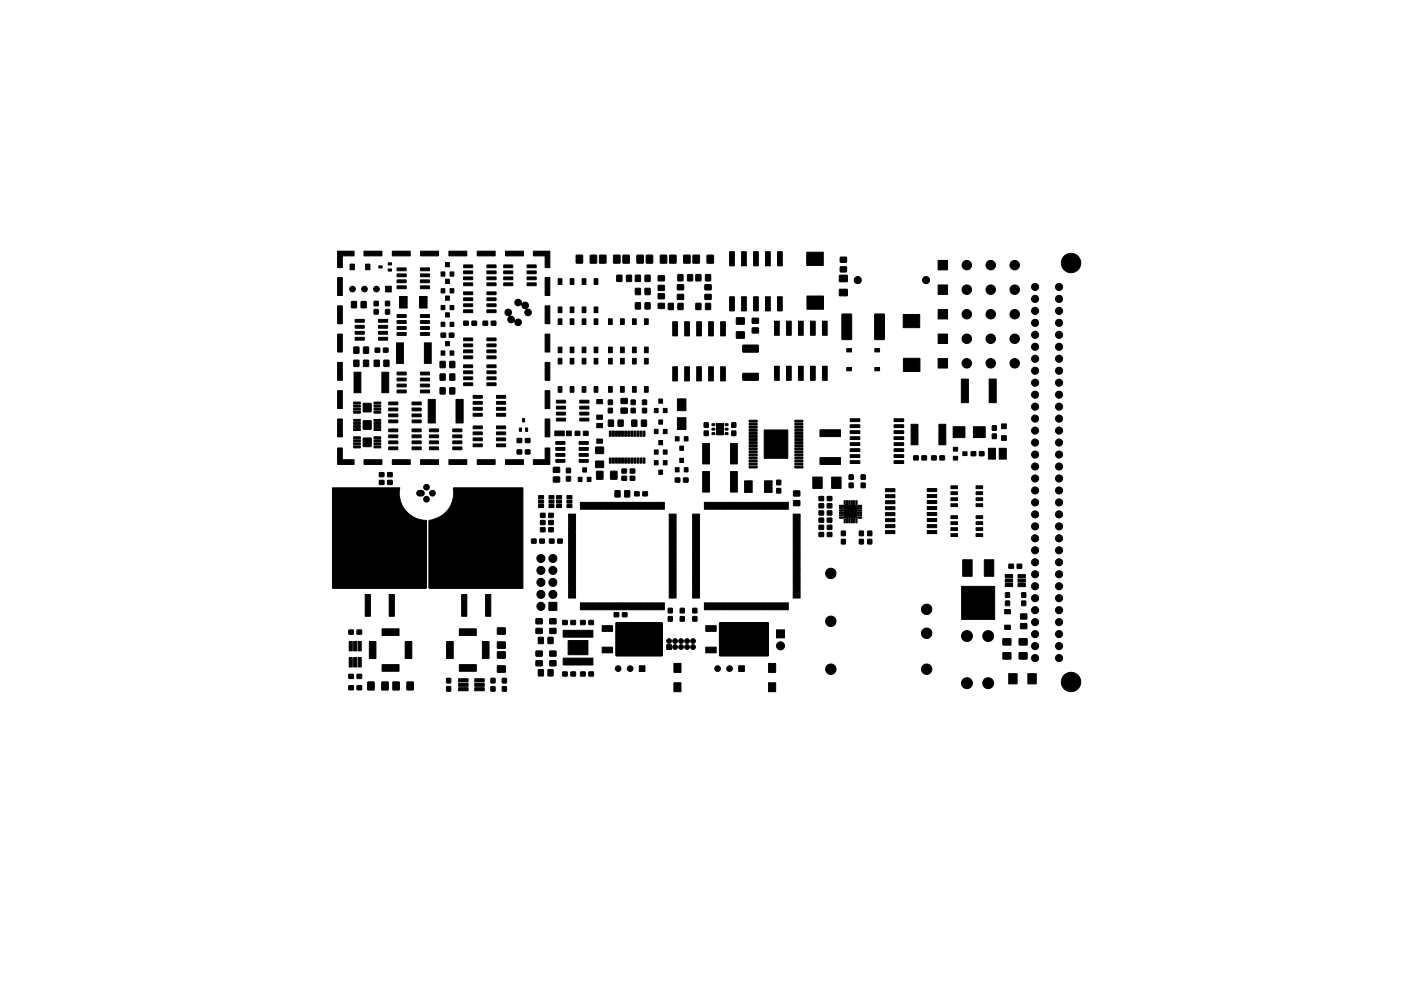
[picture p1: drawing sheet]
<svg xmlns="http://www.w3.org/2000/svg" width="297mm" height="210mm" viewBox="0 0 297 210" stroke-linecap="round" stroke-linejoin="round" font-family="sans-serif">
<g fill="#000" stroke="#000" stroke-width=".21">
<path d="M71.6 53.3h3.5v1h-2.5v2.5h-1zM74.2 56h.9v1.2h-.9zM77.5 56h.9v1.2h-.9zM77.2 53.3h3.8v1h-3.8zM80.3 56.4h.7v.5h-.7zM82.3 57.1h.7v.4h-.7zM82.3 55.8h.7v.4h-.7zM84.2 59.4h1.9v.5l-1.8 .1zM84.2 58.1h1.9v.5l-1.8 .1zM84.2 56.9l1.9-.1v.6h-1.8zM83.2 53.3h3.8v1h-3.8zM89.2 59.4h1.8l.1 .5-1.9 .1z"/>
<path d="M89.2 58.1h1.8l.1 .5-1.9 .1zM89.2 56.9l1.8-.1 .1 .6h-1.9zM89.2 53.3h3.8v1h-3.8zM93.5 57.7h.8v.9h-.8zM94.5 55.7h.8v.9h-.8zM95.4 57.7h.8v.9h-.8zM95.2 53.3h3.8v1h-3.8zM98.3 58.8h1.9v.5h-1.9zM98.3 57.5h1.9v.5l-1.9 .1zM98.3 56.2h1.9v.5l-1.9 .1zM101.2 53.3h3.8v1h-3.8zM103.3 58.8h1.8l.1 .5h-1.9z"/>
<path d="M103.3 57.5h1.8l.1 .5-1.9 .1zM103.3 56.2h1.8l.1 .5-1.9 .1zM106.8 58.8h1.9v.5h-1.8zM106.8 57.5h1.9v.5l-1.8 .1zM106.8 56.2h1.9v.5l-1.8 .1zM107.2 53.3h3.8v1h-3.8zM111.8 58.8h1.8l.1 .5h-1.9zM111.8 57.5h1.8l.1 .5-1.9 .1zM111.8 56.2h1.8l.1 .5-1.9 .1zM113.1 53.3h3.5v3.5h-1l-.1-2.5h-2.4zM122.2 54.2h1.3v1.6h-1.3zM125.2 54.2h1.3v1.6h-1.4z"/>
<path d="M127.1 54.2h1.4l-.1 1.6h-1.3zM130.1 54.2h1.4l-.1 1.6h-1.3zM130.8 58.4h1.1l-.1 1.3h-1zM132.1 54.2h1.3v1.6h-1.3zM132.8 58.4h1.1v1.3h-1.1zM134.7 58.4h1.1l-.1 1.3h-1zM135.1 54.2h1.3v1.6h-1.4zM136.8 58.4h1v1.3h-1zM137 54.2h1.4l-.1 1.6h-1.3zM139.6 58.5h1.2l.1 1-1.3 .1zM140 54.2h1.4l-.1 1.6h-1.3zM142 54.2h1.3v1.6h-1.3z"/>
<path d="M143.7 58.3h1.1v1.3l-1.1-.1zM145 54.2h1.3v1.6h-1.4zM145.8 58.3h1.1l-.1 1.3-1-.1zM146.9 54.2h1.4l-.1 1.6h-1.3zM147.6 58.3h1v1.3l-1.1-.1zM149.6 58.3h1.1l-.1 1.3-1-.1zM149.9 54.2h1.4l-.1 1.6h-1.3zM154.7 53.4h1v3h-1zM157.2 53.4h1v3h-1zM159.8 53.4h1v3h-1zM162.3 53.4h1v3h-1zM164.9 53.4h1v3h-1z"/>
<path d="M171 53.5h3.5v2.8h-3.5zM178.2 56.6h1.2l.1 1-1.3 .1zM178.2 54.6h1.2l.1 1h-1.3zM178 58.4h1.6l.1 1.3-1.7 .1zM198.9 55.3h2v2h-2zM71.6 70.9h1v3.8h-1zM71.6 64.9h1v3.8h-1zM71.6 58.9h1v3.8h-1zM74.5 64h1.1l-.1 1.3h-1zM75 76.4l1.1 .1v1.3l-1.1-.1zM75 73.6l1.1 .1v1.3l-1.1-.1zM75.3 71.6h1.9v.5l-1.8 .1z"/>
<path d="M75.3 70.3h1.9v.5l-1.8 .1zM75.3 69.1l1.9-.1v.6h-1.8zM75.3 67.8h1.9v.5l-1.8 .1zM76.6 64h1v1.3h-1zM77.1 76.4l1.1 .1-.1 1.3-1-.1zM77.1 73.6l1.1 .1-.1 1.3-1-.1zM79.3 65.7h.9v.9h-.9zM79.3 63.9h.9v1h-.9zM79.4 76.4l1 .1v1.3l-1.1-.1zM79.6 73.9h.9v.8h-.9zM80.3 71.6h1.8l.1 .5-1.9 .1zM80.3 70.3h1.8l.1 .5-1.9 .1z"/>
<path d="M80.3 69.1l1.8-.1 .1 .6h-1.9zM80.3 67.8h1.8l.1 .5-1.9 .1zM81.3 73.9h.9v.8h-.9zM81.4 76.4l1.1 .1-.1 1.3-1-.1zM81.7 65.7h.9v.9h-.9zM81.7 63.9h.9v1h-.9zM81.8 60.7h1.2v1.2h-1.2zM84.1 72.7h1.4v4.4h-1.4zM84.2 79l1.9-.1v.6h-1.8zM84.2 70.6h1.9v.5l-1.8 .1zM84.2 69.3h1.9v.5l-1.8 .1zM84.2 68h1.9v.5l-1.8 .1z"/>
<path d="M84.2 66.8h1.9v.5h-1.8zM84.2 60.7h1.9v.5l-1.8 .1zM84.7 62.9h1.6v2.4h-1.6zM88.9 62.9h1.6v2.4h-1.6zM89.2 79l1.8-.1 .1 .6h-1.9zM89.2 70.6h1.8l.1 .5-1.9 .1zM89.2 69.3h1.8l.1 .5-1.9 .1zM89.2 68h1.8l.1 .5-1.9 .1zM89.2 66.8h1.8l.1 .5h-1.9zM89.2 60.7h1.8l.1 .5-1.9 .1zM90 72.7h1.4v4.4h-1.4zM93.3 79.4h1.1l-.1 1.3-1-.1z"/>
<path d="M93.3 76.7h1.1l-.1 1.3h-1zM93.5 74.5h.8v.9h-.8zM93.5 68.4h.8v.9h-.8zM93.5 64.8h.8v.9h-.8zM93.5 61.3h.8v.9h-.8zM93.5 70.7h1v.8h-1zM94.5 72.5h.8v.9h-.8zM94.5 66.4h.8v.9h-.8zM94.5 62.8h.8v.9h-.8zM94.5 59.3h.8v.9h-.8zM95.3 70.7h.9v.8h-.9zM95.4 74.5h.8v.9h-.8z"/>
<path d="M95.4 68.4h.8v.9h-.8zM95.4 64.8h.8v.9h-.8zM95.4 61.3h.8v.9h-.8zM95.4 79.4h1v1.3l-1.1-.1zM95.4 76.7h1v1.3h-1.1zM98.3 68.2h1v.8h-1zM98.3 80h1.9v.5l-1.9 .1zM98.3 78.7h1.9v.5l-1.9 .1zM98.3 77.4h1.9v.5l-1.9 .1zM98.3 75.5h1.9v.5l-1.9 .1zM98.3 74.3l1.9-.1v.6h-1.9zM98.3 73h1.9v.5l-1.9 .1z"/>
<path d="M98.3 71.7h1.9v.5l-1.9 .1zM98.3 65.8l1.9-.1v.6h-1.9zM98.3 64.5h1.9v.5l-1.9 .1zM98.3 63.2h1.9v.5l-1.9 .1zM98.3 62l1.9-.1v.6h-1.9zM98.3 60h1.9v.5l-1.9 .1zM100.1 68.2h.9v.8h-.9zM102.4 68.2h1v.8h-1zM104.2 68.2h.9v.8h-.9zM103.3 80h1.8l.1 .5-1.9 .1zM103.3 78.7h1.8l.1 .5-1.9 .1zM103.3 77.4h1.8l.1 .5-1.9 .1z"/>
<path d="M103.3 75.5h1.8l.1 .5-1.9 .1zM103.3 74.3l1.8-.1 .1 .6h-1.9zM103.3 73h1.8l.1 .5-1.9 .1zM103.3 71.7h1.8l.1 .5-1.9 .1zM103.3 65.8l1.8-.1 .1 .6h-1.9zM103.3 64.5h1.8l.1 .5-1.9 .1zM103.3 63.2h1.8l.1 .5-1.9 .1zM103.3 62l1.8-.1 .1 .6h-1.9zM103.3 60h1.8l.1 .5-1.9 .1zM107.3 65.7a.75 .75 0 0 1 1.1 .3 .75 .75 0 0 1-.3 1v.1a.93 .93 0 0 1 1.1 .9 .7 .7 0 0 1 1-.2 .7 .7 0 0 1 .1 1.1 .7 .7 0 0 1-1.1-.3l-.1-.5a.78 .78 0 0 1-1.2 .2 .78 .78 0 0 1 .1-1.2v-.1a.76 .76 0 0 1-.8-.4 .76 .76 0 0 1 .1-.9zM106.8 60h1.9v.5l-1.8 .1zM109.3 63.7a.78 .78 0 0 1 .9-.1 .78 .78 0 0 1 .4 .8l.1 .1a.77 .77 0 0 1 1.2-.2 .77 .77 0 0 1-.2 1.2v.1a.7 .7 0 0 1 1 .5 .7 .7 0 0 1-.8 .8 .7 .7 0 0 1-.5-1.1l.2-.3a.94 .94 0 0 1-1-1 .74 .74 0 0 1-1.1 .3 .74 .74 0 0 1-.2-1.1z"/>
<path d="M111.8 60h1.8l.1 .5-1.9 .1zM115.6 70.9h1v3.8h-1zM115.6 64.9h1v3.8h-1zM115.6 58.9h1v3.8h-1zM118.3 76h.8v1.2h-.8zM118.3 73.6h.8v1.2h-.8zM118.3 67.6h.8v1.2h-.8zM118.3 65.1h.8v1.2h-.8zM118.3 59.1h.8v1.2h-.8zM120.9 76h.8v1.2h-.8zM120.9 73.6h.8v1.2h-.8zM120.9 67.6h.8v1.2h-.8z"/>
<path d="M120.9 65.1h.8v1.2h-.8zM120.9 59.1h.8v1.2h-.8zM123.4 76h.8v1.2h-.8zM123.4 73.6h.8v1.2h-.8zM123.4 67.6h.8v1.2h-.8zM123.4 65.1h.8v1.2h-.8zM123.4 59.1h.8v1.2h-.8zM126 76h.8v1.2h-.8zM126 73.6h.8v1.2h-.8zM126 67.6h.8v1.2h-.8zM126 65.1h.8v1.2h-.8zM126 59.1h.8v1.2h-.8z"/>
<path d="M129 76h.8v1.2h-.8zM129 73.6h.8v1.2h-.8zM129 67.6h.8v1.2h-.8zM131.6 76h.8v1.2h-.8zM131.6 73.6h.8v1.2h-.8zM131.6 67.6h.8v1.2h-.8zM134.1 76h.8v1.2h-.8zM134.1 73.6h.8v1.2h-.8zM134.1 67.6h.8v1.2h-.8zM134.7 64.2l1.1 .1-.1 1.3-1-.1zM134.7 61.2h1.1l-.1 1.3h-1zM136.6 76h.8v1.2h-.8z"/>
<path d="M136.6 73.6h.8v1.2h-.8zM136.6 67.6h.8v1.2h-.8zM136.8 64.2l1 .1v1.3l-1-.1zM136.8 61.2h1v1.3h-1zM139.6 64.4h1.2l.1 1h-1.3zM139.6 62.3h1.2l.1 1-1.3 .1zM139.6 60.6l1.2-.1 .1 1.1h-1.3zM141.7 64.4h1.1l-.1 1.3-1-.1zM142.6 68.3h1v3h-1zM143.8 64.4h1v1.3l-1.1-.1zM143.6 62.5h1.3v1h-1.2zM143.6 60.4h1.3v1l-1.2 .1z"/>
<path d="M145.2 68.3h1v3h-1zM147.6 64.4h1v1.3l-1.1-.1zM147.7 68.3h1v3h-1zM149.6 64.4h1.1l-.1 1.3-1-.1zM149.5 62.5h1.2l.1 1h-1.3zM149.5 60.4h1.2l.1 1-1.3 .1zM150.2 68.3h1v3h-1zM152.8 68.3h1v3h-1zM154.7 63h1v3h-1zM156.1 70.4h1.7v1.3l-1.6 .1zM156.1 67.4h1.7v1.3l-1.6 .1zM157.2 63h1v3h-1z"/>
<path d="M157.5 79.2h3.2l.1 1.4-3.2 .1zM157.5 73.3l3.2-.1 .1 1.4-3.2 .1zM159.5 69.6h1.3v1l-1.3 .1zM159.5 67.5h1.3v1.1h-1.3zM159.8 63h1v3h-1zM162.3 63h1v3h-1zM164.2 68.1h1v3h-1zM164.9 63h1v3h-1zM166.8 68.1h1v3h-1zM169.3 68.1h1v3h-1zM171.8 68.1h1v3h-1zM171.1 62.8h3.5v2.8h-3.5z"/>
<path d="M174.4 68.1h1v3h-1zM178 61.4h1.6l.1 1.3h-1.7zM178.5 66.7h2.1l-.1 5.3h-2zM179.5 78h1v.7h-1zM179.5 74h1v.7h-1zM185.5 78h1v.7h-1zM185.5 74h1v.7h-1zM185.5 66.7h2l-.1 5.3h-2zM191.5 66.7h3.5v2.8h-3.5zM191.5 76h3.5v2.8h-3.5zM198.9 76.1h2v2h-2zM198.9 70.9h2v2h-2z"/>
<path d="M198.9 65.7h2v2h-2zM198.9 60.5h2v2h-2zM71.6 95h1v2.5h2.5v1h-3.5zM71.6 88.9h1v3.8h-1zM71.6 82.9h1v3.8h-1zM71.6 76.9h1v3.8h-1zM75 94.6h1.4v.4h-1.4zM75 94h1.4v.3l-1.4 .1zM75 93.3h1.4v.4h-1.4zM75 92.7h1.4v.3l-1.4 .1zM75 91l1.4-.1v.4h-1.4zM75 90.3h1.4v.4h-1.4z"/>
<path d="M75 89.7l1.4-.1v.4h-1.4zM75 89h1.4v.4h-1.4zM75 87.3h1.4v.3l-1.4 .1zM75 86.6h1.4v.4h-1.4zM75 86h1.4v.3l-1.4 .1zM75 85.3h1.4v.4h-1.4zM75.1 79h1.4v4.3h-1.4zM77 93h1.7v1.7h-1.7zM77 89.3h1.7v1.7h-1.7zM77 85.6h1.7v1.8h-1.7zM79.3 94.6h1.4v.4h-1.4zM79.3 94h1.4v.3l-1.4 .1z"/>
<path d="M79.3 93.3h1.4v.4h-1.4zM79.3 92.7h1.4v.3l-1.4 .1zM79.3 91l1.4-.1v.4h-1.4zM79.3 90.3h1.4v.4h-1.4zM79.3 89.7l1.4-.1v.4h-1.4zM79.3 89h1.4v.4h-1.4zM79.3 87.3h1.4v.3l-1.4 .1zM79.3 86.6h1.4v.4h-1.4zM79.3 86h1.4v.3l-1.4 .1zM79.3 85.3h1.4v.4h-1.4zM77.2 97.5h3.8v1h-3.8zM81 79h1.4v4.3h-1.4z"/>
<path d="M82.4 94.8h1.9v.5l-1.8 .1zM82.4 93.6l1.9-.1v.6h-1.8zM82.4 92.3h1.9v.5l-1.8 .1zM82.4 91h1.9v.5l-1.8 .1zM82.4 89.1h1.9v.5l-1.8 .1zM82.4 87.9l1.9-.1v.6h-1.8zM82.4 86.6h1.9v.5l-1.8 .1zM82.4 85.3h1.9v.5l-1.8 .1zM84.2 82.8h1.9v.5l-1.8 .1zM84.2 81.5h1.9v.5l-1.8 .1zM84.2 80.2h1.9v.5l-1.8 .1zM83.2 97.5h3.8v1h-3.8z"/>
<path d="M87.4 94.8h1.8l.1 .5-1.9 .1zM87.4 93.6l1.8-.1 .1 .6h-1.9zM87.4 92.3h1.8l.1 .5-1.9 .1zM87.4 91h1.8l.1 .5-1.9 .1zM87.4 89.1h1.8l.1 .5-1.9 .1zM87.4 87.9l1.8-.1 .1 .6h-1.9zM87.4 86.6h1.8l.1 .5-1.9 .1zM87.4 85.3h1.8l.1 .5-1.9 .1zM89.2 82.8h1.8l.1 .5-1.9 .1zM89.2 81.5h1.8l.1 .5-1.9 .1zM89.2 80.2h1.8l.1 .5-1.9 .1zM90.8 84.7h1.5v5h-1.5z"/>
<path d="M91.1 94.8h1.8l.1 .5-1.9 .1zM91.1 93.6l1.8-.1 .1 .6h-1.9zM91.1 92.3h1.8l.1 .5-1.9 .1zM91.1 91h1.8l.1 .5-1.9 .1zM89.2 97.5h3.8v1h-3.8zM93.3 82.3h1.1l-.1 1.3-1-.1zM95.4 82.3h1v1.3l-1.1-.1zM96 94.8h1.9v.5l-1.8 .1zM96 93.6l1.9-.1v.6h-1.8zM96 92.3h1.9v.5l-1.8 .1zM96 91h1.9v.5l-1.8 .1zM96.7 84.7h1.5v5h-1.5z"/>
<path d="M95.2 97.5h3.8v1h-3.8zM98.3 81.3l1.9-.1v.6h-1.9zM100.3 94.2h1.9l.1 .5-1.9 .1zM100.3 92.9h1.9l.1 .5-1.9 .1zM100.3 91.7l1.9-.1 .1 .6h-1.9zM100.3 90.4h1.9l.1 .5-1.9 .1zM100.3 87.7h1.9l.1 .5-1.9 .1zM100.3 86.5l1.9-.1 .1 .6h-1.9zM100.3 85.2h1.9l.1 .5-1.9 .1zM100.3 83.9h1.9l.1 .5-1.9 .1zM101.2 97.5h3.8v1h-3.8zM103.3 81.3l1.8-.1 .1 .6h-1.9z"/>
<path d="M105.3 94.2h1.8l.1 .5-1.9 .1zM105.3 92.9h1.8l.1 .5-1.9 .1zM105.3 91.7l1.8-.1 .1 .6h-1.9zM105.3 90.4h1.8l.1 .5-1.9 .1zM105.3 87.7h1.8l.1 .5-1.9 .1zM105.3 86.5l1.8-.1 .1 .6h-1.9zM105.3 85.2h1.8l.1 .5-1.9 .1zM105.3 83.9h1.8l.1 .5-1.9 .1zM109.6 95.5h1v.8h-1zM109.6 93h1v.9h-1zM110.1 90.8h.5v.7h-.5zM107.2 97.5h3.8v1h-3.8z"/>
<path d="M110.8 88.8h.4v.7h-.4zM111.4 90.8h.5v.7h-.5zM111.4 95.5h.9v.8h-.9zM111.4 93h.9v.9h-.9zM113.1 97.5h2.4l.1-2.5h1v3.5h-3.5zM115.6 88.9h1v3.8h-1zM115.6 82.9h1v3.8h-1zM115.6 76.9h1v3.8h-1zM117.3 99.2l1.3-.1 .1 1.1h-1.3zM118.3 82h.8v1.2h-.8zM117.6 91.4h2v1h-2zM117.9 97.5h1.8l.1 .5-1.9 .1z"/>
<path d="M117.9 96.2h1.8l.1 .5-1.9 .1zM117.9 95l1.8-.1 .1 .6h-1.9zM117.9 93.7h1.8l.1 .5-1.9 .1zM118 88.7h1.8l.1 .6h-1.9zM118 87.5h1.8l.1 .5h-1.9zM118 86.2h1.8l.1 .5-1.9 .1zM118 84.9h1.8l.1 .5-1.9 .1zM120.1 99.4h.8v.9h-.8zM120.1 91.4h1v1h-1zM120.9 82h.8v1.2h-.8zM122 91.5h.9v.9h-.9zM123.4 82h.8v1.2h-.8z"/>
<path d="M123.7 91.5h1v.9h-1zM122.8 97.5h1.9v.5l-1.8 .1zM122.8 96.2h1.9v.5l-1.8 .1zM122.8 95l1.9-.1v.6h-1.8zM122.8 93.7h1.9v.5l-1.8 .1zM122.9 88.7h1.9l.1 .6h-1.9zM122.9 87.5h1.9l.1 .5h-1.9zM122.9 86.2h1.9l.1 .5-1.9 .1zM122.9 84.9h1.9l.1 .5-1.9 .1zM126 82h.8v1.2h-.8zM126.5 93.1h1.2v.9h-1.2zM126.5 89.8h1.2v.9h-1.2z"/>
<path d="M126.5 88.1h1.2v.9h-1.2zM126.5 84.8h1.2v.9h-1.2zM126.5 100h1.3v1.7l-1.3-.1zM126.3 97.8h1.6l.1 1.3-1.7 .1zM126.3 94.9h1.6l.1 1.3h-1.7zM129.2 97.2h.4v1.1h-.4zM129.2 91.5h.4v1.1h-.4zM129 86.6h.8v1h-.8zM129 84.9h.8v.9h-.8zM129 82h.8v1.2h-.8zM129 89.1l1.1 .1-.1 1.3-1-.1zM129.8 97.2h.4v1.1h-.4z"/>
<path d="M129.8 91.5h.4v1.1h-.4zM129.5 100h1.3v1.7l-1.3-.1zM130.5 97.2h.4v1.1h-.4zM130.5 91.5h.4v1.1h-.4zM131.1 97.2h.4v1.1h-.4zM131.1 91.5h.4v1.1h-.4zM131.1 89.1l1 .1v1.3l-1.1-.1zM131.8 97.2h.4v1.1h-.4zM131.8 91.5h.4v1.1h-.4zM131.6 82h.8v1.2h-.8zM131.9 99.5h.9v.9h-.9zM132.4 97.2h.4v1.1h-.4z"/>
<path d="M132.4 91.5h.4v1.1h-.4zM131.7 86.6h1.3v1l-1.3 .1zM131.7 84.6l1.3-.1v1.1h-1.3zM133.1 97.2h.4v1.1h-.4zM133.1 91.5h.4v1.1h-.4zM133.7 97.2h.4v1.1h-.4zM133.7 91.5h.4v1.1h-.4zM133.6 99.5h1v.9h-1zM133.8 86.6h.9v1h-.9zM133.8 84.9h.9v.9h-.9zM134.4 97.2h.4v1.1h-.4zM134.4 91.5h.4v1.1h-.4z"/>
<path d="M134.1 82h.8v1.2h-.8zM134 89.1l1 .1v1.3l-1.1-.1zM135 97.2h.4v1.1h-.4zM135 91.5h.4v1.1h-.4zM135.7 97.2h.4v1.1h-.4zM135.7 91.5h.4v1.1h-.4zM136.3 97.2h.4v1.1h-.4zM136.3 91.5h.4v1.1h-.4zM136 89.1l1.1 .1-.1 1.3-1-.1zM136.2 86.6h.9v1h-.9zM136.2 84.9h.9v.9h-.9zM136.6 82h.8v1.2h-.8z"/>
<path d="M138.7 97.7h.8v.9h-.8zM138.7 95.5h.8v.9h-.8zM138.7 91.1h.8v.9h-.8zM138.7 86.7h.8v.9h-.8zM139.7 93.5h.8v.9h-.8zM139.7 89.1h.8v.9h-.8zM139.7 84.7h.8v.9h-.8zM140.6 97.7h.8v.9h-.8zM140.6 95.5h.8v.9h-.8zM140.6 91.1h.8v.9h-.8zM140.6 86.7h.8v.9h-.8zM142.6 77.8h1v3h-1z"/>
<path d="M143.2 92.7h.8v.9h-.8zM144.1 97.2h.8v.9h-.8zM144.1 94.7h.8v.9h-.8zM143.6 88.6h1.8v2.5h-1.8zM143.6 84.6h1.8v2.5h-1.8zM145.1 92.7h.8v.9h-.8zM145.2 77.8h1v3h-1zM147.7 77.8h1v3h-1zM149.3 91.5h.9v.9h-.9zM149.3 89.7h.9v1h-.9zM149 94.1h1.4v4.3h-1.4zM150.2 77.8h1v3h-1z"/>
<path d="M151 91.8h.6v.4h-.6zM151 90.9h.6v.4h-.6zM151 89.9h.6v.4h-.6zM151.9 89.9h1.5v2.4h-1.5zM152.8 77.8h1v3h-1zM153.8 91.8h.6v.4h-.6zM153.8 90.9h.6v.4h-.6zM153.8 89.9h.6v.4h-.6zM155.2 91.5h.8v.9h-.8zM155.2 89.7h.8v1h-.8zM154.9 94.1h1.4v4.3h-1.4zM158.8 98.9h1.7v.4h-1.7z"/>
<path d="M158.8 98.3h1.7v.3h-1.7zM158.8 97.6h1.7v.4h-1.7zM158.8 97h1.7v.3h-1.7zM158.8 96.3h1.7v.4h-1.7zM158.8 95.7h1.7v.3h-1.7zM158.8 95h1.7v.4h-1.7zM158.8 94.4h1.7v.3h-1.7zM158.8 93.7h1.7v.4h-1.7zM158.8 93.1h1.7v.3h-1.7zM158.8 92.4h1.7v.4h-1.7zM158.8 91.8h1.7v.3h-1.7zM158.8 91.1h1.7v.4h-1.7z"/>
<path d="M158.8 90.5h1.7v.3h-1.7zM158.8 89.8h1.7v.4h-1.7zM158.8 89.2h1.7v.3h-1.7zM164.2 77.7h1v3h-1zM162 91.2h5v6h-5zM166.8 77.7h1v3h-1zM168.5 98.9h1.7v.4h-1.7zM168.5 98.3h1.7v.3h-1.7zM168.5 97.6h1.7v.4h-1.7zM168.5 97h1.7v.3h-1.7zM168.5 96.3h1.7v.4h-1.7zM168.5 95.7h1.7v.3h-1.7z"/>
<path d="M168.5 95h1.7v.4h-1.7zM168.5 94.4h1.7v.3h-1.7zM168.5 93.7h1.7v.4h-1.7zM168.5 93.1h1.7v.3h-1.7zM168.5 92.4h1.7v.4h-1.7zM168.5 91.8h1.7v.3h-1.7zM168.5 91.1h1.7v.4h-1.7zM168.5 90.5h1.7v.3h-1.7zM168.5 89.8h1.7v.4h-1.7zM168.5 89.2h1.7v.3h-1.7zM169.3 77.7h1v3h-1zM171.8 77.7h1v3h-1z"/>
<path d="M174.4 77.7h1v3h-1zM173.8 97.1h4.4v1.4h-4.4zM173.8 91.2h4.4v1.4h-4.4zM180.3 97.8l1.9-.1 .1 .6h-2zM180.3 96.5h1.9l.1 .5-2 .1zM180.3 95.2h1.9l.1 .5-2 .1zM180.3 94l1.9-.1 .1 .6h-2zM180.3 92.7h1.9l.1 .5-2 .1zM180.3 91.4h1.9l.1 .5-2 .1zM180.3 90.1h1.9l.1 .5-2 .1zM180.3 88.9h1.9l.1 .5h-2zM189.6 97.8l1.9-.1 .1 .6h-2z"/>
<path d="M189.6 96.5h1.9l.1 .5-2 .1zM189.6 95.2h1.9l.1 .5-2 .1zM189.6 94l1.9-.1 .1 .6h-2zM189.6 92.7h1.9l.1 .5-2 .1zM189.6 91.4h1.9l.1 .5-2 .1zM189.6 90.1h1.9l.1 .5-2 .1zM189.6 88.9h1.9l.1 .5h-2zM193.7 96.7h1v.9h-1zM193.2 90h1.4v4.4h-1.4zM195.5 96.7h.9v.9h-.9zM197.5 96.7h1v.9h-1zM199.3 96.7h.9v.9h-.9z"/>
<path d="M199.1 90h1.4v4.4h-1.4zM202.1 96.8h.9v.8h-.9zM202.1 94.9h.9v.8h-.9zM202.1 90.5h2.5v2.3h-2.5zM204.1 95.9h.9v.8h-.9zM203.8 80.4h1.5v5h-1.5zM205.9 95.8h1v.9h-1zM207.7 95.8h.9v.9h-.9zM206.4 90.5h2.5v2.3h-2.5zM209.6 95.1h1.5v2.3h-1.5zM210.4 92.1h.8v.9h-.8zM210.4 90.3h.8v1h-.8z"/>
<path d="M209.7 80.4h1.5v5h-1.5zM211.8 95.1h1.5v2.3h-1.5zM212.4 92.4h1v1h-1zM212.4 89.9h1v1h-1zM80.4 101.9h1v.9h-1zM80.4 100.3h1v.8h-1zM82.2 101.9h.9v.9h-.9zM82.2 100.3h.9v.8h-.9zM70.5 103.5h14.3l-.2 1.6 .3 1.3 .4 .9 .6 1 1.1 1a5.4 5.4 0 0 0 2.7 1.1h.7v14.3l-.1 .1h-19.7l-.1-.1zM88.5 104.2l.9-.2a.6 .6 0 0 1 .6 .6 .6 .6 0 0 1-.6 .6h-.5a.6 .6 0 0 1-.5-.3 .6 .6 0 0 1 .1-.7zM112.7 114.4h.9v.8h-.9zM114.2 107h1.1v.7h-1.1z"/>
<path d="M114.2 106.1h1.1v.6h-1.1zM114.2 105.1h1.1v.7h-1.1zM114.4 114.4h1v.8h-1zM114.6 112h.9v.8h-.9zM114.6 110.4h.9v.9h-.9zM114.6 108.9h.9v.9h-.9zM116.4 112h.9v.8h-.9zM116.4 110.4h.9v.9h-.9zM116.4 108.9h.9v.9h-.9zM116.5 114.4h1v.8h-1zM116.4 107h1.1v.7h-1.1zM116.4 106.1h1.1v.6h-1.1z"/>
<path d="M116.4 105.1h1.1v.7h-1.1zM117.3 101.2h1.3l.1 1-1.3 .1zM118 107h1.1v.7h-1.1zM118 106.1h1.1v.6h-1.1zM118 105.1h1.1v.7h-1.1zM118.3 114.4h.9v.8h-.9zM120.1 101.1h.8v1h-.8zM120.2 107h1.1v.7h-1.1zM120.2 106.1h1.1v.6h-1.1zM120.2 105.1h1.1v.7h-1.1zM120.6 109.1h1.4v17.8h-1.4zM123.1 106.6h17.7l.1 1.4-17.8 .1z"/>
<path d="M122.6 101.3h.8v.9h-.8zM123.6 99.3h.8v.9h-.8zM124.5 101.3h.8v.9h-.8zM130.4 104.1h1.1l-.1 1.3h-1zM131.9 101h.9v.9h-.9zM132.5 104.1h1v1.3h-1.1zM133.6 101h1v.9h-1zM134.6 104.3h.9v.9h-.9zM136.3 104.3h1v.9h-1zM139.7 99.7h.8v.9h-.8zM141.9 109.1h1.5l-.1 17.8h-1.4zM143.2 99.2h.8v.9h-.8z"/>
<path d="M143.2 101.4h.9v.9h-.9zM144.9 101.4h1v.9h-1zM145.1 99.2h.8v.9h-.8zM146.8 109.1h1.5v17.8h-1.5zM149.3 106.6h17.8v1.4l-17.7 .1zM149 100.1h1.4v4.3h-1.4zM154.9 100.1h1.4v4.3h-1.4zM157.9 102h1.6v2.5l-1.6-.1zM162.1 102h1.6v2.5l-1.6-.1zM164.7 103.6h.8v1h-.8zM164.7 101.9h.8v.9h-.8zM168.3 106.2h1.2l.1 1-1.3 .1z"/>
<path d="M168.3 104.2h1.2l.1 1h-1.3zM168.2 109.1h1.4v17.8h-1.4zM172.3 101.2h2v2.4h-2zM173.7 113h.9v.8h-.9zM173.7 111.5h.9v.8h-.9zM173.7 109.9h.9v.9h-.9zM173.7 108.4h.9v.9h-.9zM173.7 106.9h.9v.8h-.9zM173.7 105.4h.9v.8h-.9zM175.4 113h1v.8h-1zM175.4 111.5h1v.8h-1zM175.4 109.9h1v.9h-1z"/>
<path d="M175.4 108.4h1v.9h-1zM175.4 106.9h1v.8h-1zM175.4 105.4h1v.8h-1zM176.3 101.2h2v2.4h-2zM178 107.2h.8l.1 .2-.9 .1zM178 109.7h.9l-.1 .3h-.8zM178.4 114.4h.8v1h-.8zM178.4 112.7h.8v.9h-.8zM179 110.1h.2v.8h-.2zM179 106.2h.2v.9h-.2zM178 107.7h1l.1-.4 .4-.1v-1h.2v1l.1 .1 .2-.1v-1h.2v1l.1 .1 .2-.1v-1h.2v1l.2 .1 .1-1.1h.2v1l.4 .1 .1 .4h1v.3l-.9-.1-.2 .1 .1 .3 1-.1v.3l-.9-.1-.2 .1 .1 .3 1-.1v.3l-1-.1-.1 .3h1.1v.3l-1-.1-.1 .4-.4 .1v1h-.2v-.9l-.1-.1-.2 .1v.9h-.2v-.9l-.1-.1-.2 .1v.9h-.2v-.9l-.3-.1v1h-.2v-.9l-.4-.2-.1-.4-1 .1v-.3l.9 .1 .1-.2-.1-.2-.9 .1v-.3l.9 .1 .1-.2-.1-.2-.9 .1v-.3h1v-.2h-1zM180 102.5h.9v1h-.9z"/>
<path d="M180 100.8h.9v.9h-.9zM181.5 110.1h.2v.8h-.2zM181.5 106.2h.2v.9h-.2zM181.8 109.7h.9v.3h-.8zM181.9 107.2h.8v.3h-.8zM182.2 114.4h.8v1h-.8zM182.2 112.7h.8v.9h-.8zM182.6 102.5h.8v1h-.8zM182.6 100.8h.8v.9h-.8zM184 114.4h.8v1h-.8zM184 112.7h.8v.9h-.8zM187.7 112.6h2v.6h-2z"/>
<path d="M187.7 111.3h2v.6h-2zM187.7 110h2v.7h-2zM187.7 108.8h2v.6h-2zM187.7 107.5h2v.6h-2zM187.7 106.2h2v.7h-2zM187.7 105h2v.6h-2zM187.7 103.7h2v.6h-2zM196.6 112.6h2v.6h-2zM196.6 111.3h2v.6h-2zM196.6 110h2v.7h-2zM196.6 108.7h2v.7h-2zM196.6 107.5h2v.6h-2z"/>
<path d="M196.6 106.2h2v.6h-2zM196.6 104.9h2v.7h-2zM196.6 103.7h2v.6h-2zM201.6 113.2h1.4v.6h-1.4zM201.6 112h1.4v.6h-1.4zM201.6 110.7h1.4v.6h-1.4zM201.6 109.4h1.4v.6h-1.4zM201.6 106.9h1.4v.6h-1.4zM201.6 105.6h1.4v.6h-1.4zM201.6 104.3h1.4v.6h-1.4zM201.6 103.1h1.4v.6h-1.4zM206.9 113.2h1.4v.6h-1.4z"/>
<path d="M206.9 112h1.4v.6h-1.4zM206.9 110.7h1.4v.6h-1.4zM206.9 109.4h1.4v.6h-1.4zM206.9 106.9h1.4v.6h-1.4zM206.9 105.6h1.4v.6h-1.4zM206.9 104.3h1.4v.6h-1.4zM206.9 103.1h1.4v.6h-1.4zM213.9 119.7h1v.9h-1zM215.7 119.7h.9v.9h-.9zM74 136.1h.7v2h-.7zM74 133.7h.9v.8h-.9zM75 136.1h.6v2h-.6z"/>
<path d="M75.7 133.7h1v.8h-1zM75.9 136.1h.7v2h-.7zM77.4 126.2h1.1v4.6h-1.1zM78.3 136.1h1.4v3.6h-1.4zM82.5 126.2h1.1v4.6h-1.1zM81 133.4h3.6v1.4h-3.6zM85.9 136.1h1.4v3.6h-1.4zM94.7 136.1h1.4v3.6h-1.4zM97.9 126.2h1.1v4.6h-1.1zM97.4 133.4h3.6v1.4h-3.6zM102.3 136.1h1.4v3.6h-1.4zM103 126.2h1.1v4.6h-1.1z"/>
<path d="M105.5 138.3h1.6v1.3l-1.6 .1zM105.5 136.2h1.6v1.3h-1.6zM105.5 133.2h1.6v1.3l-1.6 .1zM96.2 103.5h14.7v21.3h-19.8l-.2-.1v-14.2l.9-.3a6.1 6.1 0 0 0 3.1-1.9l.7-1.2 .4-1.1zM113.7 138.1h1.2l.1 1.1h-1.3zM113.7 133.3h1.2l.1 1.1h-1.3zM113.7 131.3h1.2l.1 1-1.3 .1zM114.1 135.2l1.1 .1v1.3l-1.1-.1zM116.2 135.2l1.1 .1-.1 1.3-1-.1zM116.6 138.1h1.2l.1 1.1h-1.3zM116.6 133.3h1.2l.1 1.1h-1.3zM116.6 131.3h1.2l.1 1-1.3 .1z"/>
<path d="M116.4 127.8h1.7v1.7h-1.7zM119.3 131.7h.9v.8h-.9zM121.1 131.7h.9v.8h-.9zM123.1 127.9h17.7l.1 1.5h-17.8zM123.1 131.7h1v.8h-1zM120.5 135.9h4.2v3h-4.2zM119.4 133.7h6.3v1.5h-6.3zM124.9 131.7h.9v.8h-.9zM127.7 137.3h2.2v1.2h-2.2zM127.7 132.8h2.2v1.2h-2.2zM130.2 130h1v.8h-1zM132 130h.9v.8h-.9z"/>
<path d="M130.6 132.2l.1-.1h9.6l.2 .1v6.9l-.2 .1h-9.6l-.1-.1zM141.4 136.8h1v1h-1zM141.7 130.8h.8v1h-.8zM141.7 129.1h.8v.9h-.8zM144.2 130.8h.9v1h-.9zM144.2 129.1h.9v.9h-.9zM146.9 130.8h.8v1h-.8zM146.9 129.1h.8v.9h-.8zM149.3 127.9h17.8v1.5h-17.7zM149.6 137.3h2.2v1.2h-2.2zM149.6 132.8h2.2v1.2h-2.2zM152.5 132.2l.2-.1h10.1l.1 .1v6.9l-.1 .1h-10.1l-.2-.1z"/>
<path d="M164.6 133.6h1.7v1.7h-1.7zM204.1 118.8h2v3.5h-2zM208.7 118.8h2v3.5h-2zM203.9 124.4h7v7h-7zM213.2 127.5h.8v1h-.8zM213.2 125.8h.8v.9h-.8zM213 132.6h1.2v.9h-1.2zM213 129.3h1.2v.9h-1.2zM212.7 138.5h1.6v1.3h-1.6zM212.7 135.5h1.6v1.3l-1.6 .1zM213.1 123.8h1.6v.7h-1.6zM213.1 122.9h1.6v.6h-1.6z"/>
<path d="M213.1 121.9h1.6v.7h-1.6zM216.6 127.5h.9v1h-.9zM216.6 125.8h.9v.9h-.9zM215.8 123.8h1.6v.7h-1.6zM215.8 122.9h1.6v.6h-1.6zM215.8 121.9h1.6v.7h-1.6zM216.4 132.3h1.3v1l-1.3 .1zM216.4 130.3h1.3v1h-1.3zM216.1 138.5h1.6l.1 1.3h-1.7zM216.1 135.5h1.6l.1 1.3-1.7 .1zM74 139.5h.7v2h-.7zM74 145.5h.9v.8h-.9z"/>
<path d="M74 143.1h.9v.8h-.9zM75 139.5h.6v2h-.6zM75.7 145.5h1v.8h-1zM75.7 143.1h1v.8h-1zM75.9 139.5h.7v2h-.7zM78 144.7h1.3v1.7l-1.3-.1zM81 144.7h1.3v1.7l-1.4-.1zM83.3 144.7h1.4l-.1 1.7-1.3-.1zM81 141h3.6v1.4h-3.6zM86.3 144.7h1.3v1.7l-1.3-.1zM94.7 145.7h.8v.9h-.8zM94.7 143.9h.8v1h-.8z"/>
<path d="M97.2 145.9h2v.7h-2zM97.2 145h2v.6h-2zM97.2 144h2v.7h-2zM97.4 141h3.6v1.4h-3.6zM100.7 145.9h2v.7h-2zM100.7 145h2v.6h-2zM100.7 144h2v.7h-2zM104.1 145.7h.8v.9h-.8zM104.1 143.9h.8v1h-.8zM105.5 141.3h1.6v1.3h-1.6zM106.5 145.7h.9v.9h-.9zM106.5 143.9h.9v1h-.9z"/>
<path d="M113.7 140.2h1.2l.1 1-1.3 .1zM114.1 142.1h1.1v1.3h-1.1zM116.2 142.1h1.1l-.1 1.3h-1zM116.6 140.2h1.2l.1 1-1.3 .1zM119.3 142.6h.9v.8h-.9zM121.1 142.6h.9v.8h-.9zM123.1 142.6h1v.8h-1zM119.4 139.6h6.3v1.5h-6.3zM124.9 142.6h.9v.8h-.9zM135.5 141.3h1.2v1.2h-1.2zM142.9 144.9h1.5v1.9h-1.5zM142.9 140.8h1.5v1.9h-1.5z"/>
<path d="M156.6 141.3h1.2v1.2h-1.2zM163 144.9h1.5v1.9h-1.5zM163 140.8h1.5v1.9h-1.5zM213.9 142.9h1.7v2.2h-1.7zM217.9 142.9h1.8v2.2h-1.8z"/>
<circle cx="181.9" cy="59.4" r=".75"/>
<circle cx="196.3" cy="59.4" r=".75"/>
<circle cx="205" cy="56.3" r="1"/>
<circle cx="210.1" cy="56.3" r="1"/>
<circle cx="215.1" cy="56.3" r="1"/>
<circle cx="227.1" cy="55.8" r="2.05"/>
<circle cx="74.7" cy="61.3" r=".6"/>
<circle cx="77.3" cy="61.3" r=".6"/>
<circle cx="79.8" cy="61.3" r=".6"/>
<circle cx="205" cy="66.7" r="1"/>
<circle cx="205" cy="61.5" r="1"/>
<circle cx="205" cy="77.1" r="1"/>
<circle cx="205" cy="71.9" r="1"/>
<circle cx="210.1" cy="66.7" r="1"/>
<circle cx="210.1" cy="61.5" r="1"/>
<circle cx="210.1" cy="77.1" r="1"/>
<circle cx="210.1" cy="71.9" r="1"/>
<circle cx="215.1" cy="66.7" r="1"/>
<circle cx="215.1" cy="61.5" r="1"/>
<circle cx="215.1" cy="77.1" r="1"/>
<circle cx="215.1" cy="71.9" r="1"/>
<circle cx="219.5" cy="78.7" r=".75"/>
<circle cx="219.5" cy="63.4" r=".75"/>
<circle cx="219.5" cy="68.5" r=".75"/>
<circle cx="219.5" cy="66" r=".75"/>
<circle cx="219.5" cy="71" r=".75"/>
<circle cx="219.5" cy="60.9" r=".75"/>
<circle cx="219.5" cy="76.1" r=".75"/>
<circle cx="219.5" cy="73.6" r=".75"/>
<circle cx="224.5" cy="78.7" r=".75"/>
<circle cx="224.5" cy="68.5" r=".75"/>
<circle cx="224.5" cy="66" r=".75"/>
<circle cx="224.5" cy="63.4" r=".75"/>
<circle cx="224.5" cy="71" r=".75"/>
<circle cx="224.5" cy="76.1" r=".75"/>
<circle cx="224.5" cy="73.6" r=".75"/>
<circle cx="224.5" cy="60.9" r=".75"/>
<circle cx="219.5" cy="88.8" r=".75"/>
<circle cx="219.5" cy="91.4" r=".75"/>
<circle cx="219.5" cy="99" r=".75"/>
<circle cx="219.5" cy="96.4" r=".75"/>
<circle cx="219.5" cy="93.9" r=".75"/>
<circle cx="219.5" cy="86.3" r=".75"/>
<circle cx="219.5" cy="81.2" r=".75"/>
<circle cx="219.5" cy="83.7" r=".75"/>
<circle cx="224.5" cy="88.8" r=".75"/>
<circle cx="224.5" cy="91.4" r=".75"/>
<circle cx="224.5" cy="99" r=".75"/>
<circle cx="224.5" cy="93.9" r=".75"/>
<circle cx="224.5" cy="81.2" r=".75"/>
<circle cx="224.5" cy="96.4" r=".75"/>
<circle cx="224.5" cy="86.3" r=".75"/>
<circle cx="224.5" cy="83.7" r=".75"/>
<circle cx="90.4" cy="105.9" r=".6"/>
<circle cx="90.4" cy="103.4" r=".6"/>
<circle cx="91.7" cy="104.6" r=".6"/>
<circle cx="114.7" cy="118.5" r=".85"/>
<circle cx="117.2" cy="118.5" r=".85"/>
<circle cx="219.5" cy="119.3" r=".75"/>
<circle cx="219.5" cy="114.2" r=".75"/>
<circle cx="219.5" cy="111.7" r=".75"/>
<circle cx="219.5" cy="109.1" r=".75"/>
<circle cx="219.5" cy="106.6" r=".75"/>
<circle cx="219.5" cy="104.1" r=".75"/>
<circle cx="219.5" cy="116.8" r=".75"/>
<circle cx="219.5" cy="101.5" r=".75"/>
<circle cx="224.5" cy="119.3" r=".75"/>
<circle cx="224.5" cy="114.2" r=".75"/>
<circle cx="224.5" cy="104.1" r=".75"/>
<circle cx="224.5" cy="111.7" r=".75"/>
<circle cx="224.5" cy="109.1" r=".75"/>
<circle cx="224.5" cy="101.5" r=".75"/>
<circle cx="224.5" cy="116.8" r=".75"/>
<circle cx="224.5" cy="106.6" r=".75"/>
<circle cx="114.7" cy="121" r=".85"/>
<circle cx="114.7" cy="128.6" r=".85"/>
<circle cx="114.7" cy="126.1" r=".85"/>
<circle cx="114.7" cy="123.6" r=".85"/>
<circle cx="117.2" cy="121" r=".85"/>
<circle cx="117.2" cy="126.1" r=".85"/>
<circle cx="117.2" cy="123.6" r=".85"/>
<circle cx="141.9" cy="136" r=".5"/>
<circle cx="143.1" cy="137.3" r=".5"/>
<circle cx="143.1" cy="136" r=".5"/>
<circle cx="144.4" cy="137.3" r=".5"/>
<circle cx="144.4" cy="136" r=".5"/>
<circle cx="145.7" cy="137.3" r=".5"/>
<circle cx="145.7" cy="136" r=".5"/>
<circle cx="146.9" cy="137.3" r=".5"/>
<circle cx="146.9" cy="136" r=".5"/>
<circle cx="165.5" cy="137" r=".85"/>
<circle cx="176.1" cy="131.8" r="1.1"/>
<circle cx="176.2" cy="121.7" r="1.1"/>
<circle cx="196.5" cy="129.3" r="1.11"/>
<circle cx="196.5" cy="134.4" r="1.1"/>
<circle cx="205" cy="135" r="1.15"/>
<circle cx="209.5" cy="135" r="1.15"/>
<circle cx="219.5" cy="121.8" r=".75"/>
<circle cx="219.5" cy="124.4" r=".75"/>
<circle cx="219.5" cy="139.6" r=".75"/>
<circle cx="219.5" cy="137.1" r=".75"/>
<circle cx="219.5" cy="129.5" r=".75"/>
<circle cx="219.5" cy="132" r=".75"/>
<circle cx="219.5" cy="134.5" r=".75"/>
<circle cx="219.5" cy="126.9" r=".75"/>
<circle cx="224.5" cy="124.4" r=".75"/>
<circle cx="224.5" cy="121.8" r=".75"/>
<circle cx="224.5" cy="139.6" r=".75"/>
<circle cx="224.5" cy="137.1" r=".75"/>
<circle cx="224.5" cy="132" r=".75"/>
<circle cx="224.5" cy="129.5" r=".75"/>
<circle cx="224.5" cy="134.5" r=".75"/>
<circle cx="224.5" cy="126.9" r=".75"/>
<circle cx="131.1" cy="141.9" r=".6"/>
<circle cx="133.6" cy="141.9" r=".6"/>
<circle cx="152.1" cy="141.9" r=".6"/>
<circle cx="154.7" cy="141.9" r=".6"/>
<circle cx="176.1" cy="142" r="1.11"/>
<circle cx="196.5" cy="142" r="1.11"/>
<circle cx="205" cy="145" r="1.15"/>
<circle cx="209.5" cy="145" r="1.15"/>
<circle cx="227.1" cy="144.7" r="2.06"/>
</g>
</svg>
